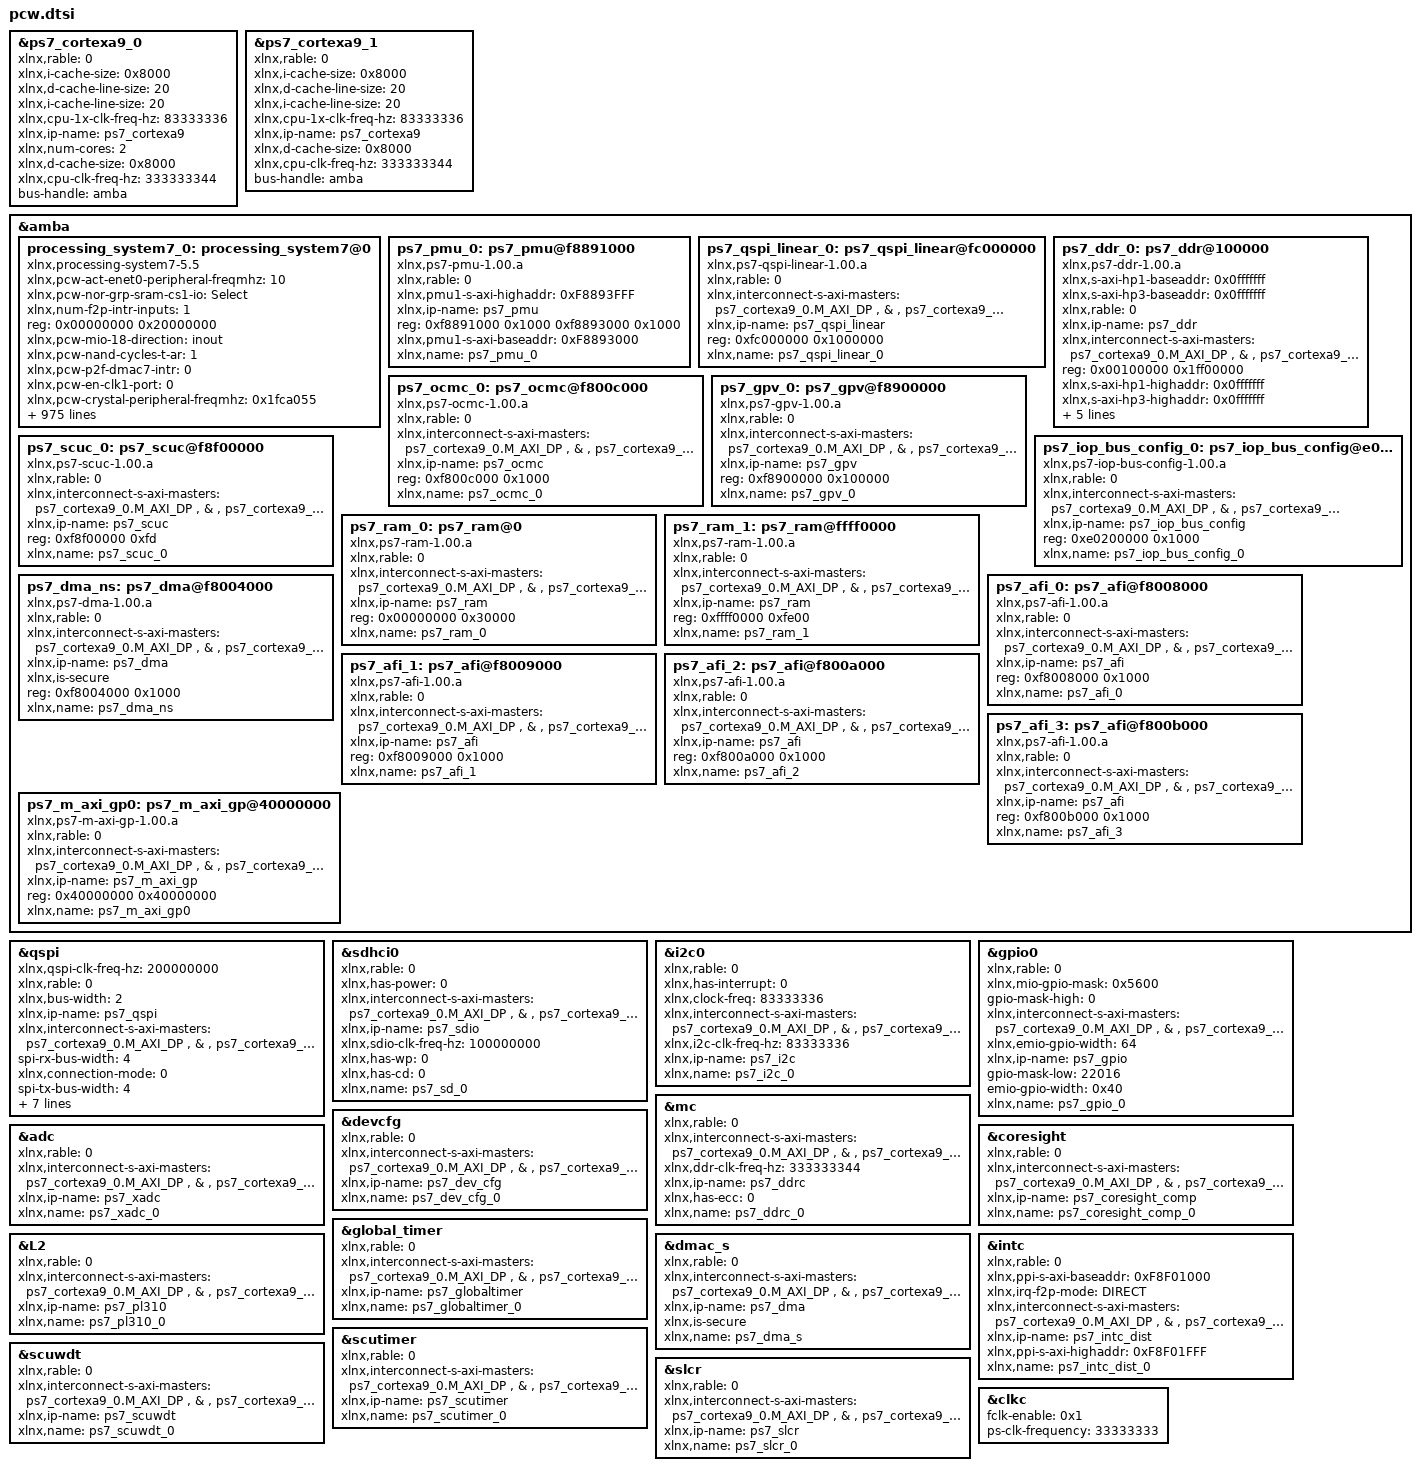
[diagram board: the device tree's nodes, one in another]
	&ps7_cortexa9_0 {
		xlnx,rable = <0>;
		xlnx,i-cache-size = <0x8000>;
		xlnx,d-cache-line-size = <20>;
		xlnx,i-cache-line-size = <20>;
		xlnx,cpu-1x-clk-freq-hz = <83333336>;
		xlnx,ip-name = "ps7_cortexa9";
		xlnx,num-cores = <2>;
		xlnx,d-cache-size = <0x8000>;
		xlnx,cpu-clk-freq-hz = <333333344>;
		bus-handle = <&amba>;
	};
	&ps7_cortexa9_1 {
		xlnx,rable = <0>;
		xlnx,i-cache-size = <0x8000>;
		xlnx,d-cache-line-size = <20>;
		xlnx,i-cache-line-size = <20>;
		xlnx,cpu-1x-clk-freq-hz = <83333336>;
		xlnx,ip-name = "ps7_cortexa9";
		xlnx,d-cache-size = <0x8000>;
		xlnx,cpu-clk-freq-hz = <333333344>;
		bus-handle = <&amba>;
	};
	&amba {
		processing_system7_0: processing_system7@0 {
			xlnx,pcw-act-enet0-peripheral-freqmhz = <10>;
			xlnx,pcw-nor-grp-sram-cs1-io = "<Select>";
			xlnx,num-f2p-intr-inputs = <1>;
			reg = <0x00000000 0x20000000>;
			xlnx,pcw-mio-18-direction = "inout";
			xlnx,pcw-nand-cycles-t-ar = <1>;
			xlnx,pcw-p2f-dmac7-intr = <0>;
			xlnx,pcw-en-clk1-port = <0>;
			xlnx,pcw-crystal-peripheral-freqmhz = <0x1fca055>;
			xlnx,pcw-nor-grp-sram-cs1-enable = <0>;
			xlnx,pcw-uiparam-ddr-dq-1-package-length = <0x4366e20>;
			xlnx,pcw-act-wdt-peripheral-freqmhz = <0x4f790d8>;
			xlnx,pcw-p2f-dmac4-intr = <0>;
			xlnx,pcw-s-axi-hp3-id-width = <6>;
			xlnx,pcw-en-emio-uart0 = <0>;
			xlnx,pcw-en-emio-uart1 = <0>;
			xlnx,pcw-ddr-hpr-to-critical-priority-level = <15>;
			xlnx,pcw-enet-reset-polarity = "Active , Low";
			xlnx,pcw-mio-5-direction = "inout";
			xlnx,pcw-p2f-dmac1-intr = <0>;
			xlnx,pcw-sd0-grp-cd-enable = <0>;
			xlnx,pcw-act-fpga1-peripheral-freqmhz = <10>;
			xlnx,pcw-mio-24-iotype = "LVCMOS , 3.3V";
			xlnx,pcw-ddr-port1-hpr-enable = <0>;
			xlnx,pcw-cpu-peripheral-clksrc = "ARM , PLL";
			xlnx,pcw-mio-53-pullup = "enabled";
			xlnx,pcw-use-axi-nonsecure = <0>;
			xlnx,pcw-spi1-grp-ss0-io = "<Select>";
			xlnx,pcw-uiparam-ddr-dqs-1-propogation-delay = <160>;
			xlnx,pcw-nor-cs1-t-pc = <1>;
			xlnx,pcw-s-axi-gp0-id-width = <6>;
			xlnx,pcw-trace-grp-8bit-io = "<Select>";
			xlnx,pcw-ttc-peripheral-freqmhz = <50>;
			xlnx,pcw-uart0-baseaddr = <0xE0000000>;
			xlnx,pcw-ftm-cti-out0 = "<Select>";
			xlnx,pcw-ttc1-clk0-peripheral-divisor0 = <1>;
			xlnx,pcw-uiparam-ddr-clock-stop-en = <0>;
			xlnx,pcw-ftm-cti-out1 = "<Select>";
			xlnx,pcw-mio-28-direction = "inout";
			xlnx,pcw-en-ttc0 = <0>;
			xlnx,pcw-ftm-cti-out2 = "<Select>";
			xlnx,pcw-mio-11-pullup = "enabled";
			xlnx,pcw-en-ttc1 = <0>;
			xlnx,pcw-ftm-cti-out3 = "<Select>";
			xlnx,pcw-m-axi-gp0-thread-id-width = <12>;
			xlnx,pcw-nor-sram-cs1-t-ceoe = <1>;
			xlnx,pcw-nor-grp-sram-int-enable = <0>;
			xlnx,pcw-can-peripheral-clksrc = "IO , PLL";
			xlnx,pcw-ttc1-clk0-peripheral-clksrc = "CPU_1X";
			xlnx,mio-primitive = <54>;
			xlnx,pcw-gp0-num-write-threads = <4>;
			xlnx,pcw-mio-4-iotype = "LVCMOS , 3.3V";
			xlnx,pcw-mio-41-iotype = "LVCMOS , 3.3V";
			xlnx,pcw-nor-cs1-t-rc = <11>;
			xlnx,pcw-i2c0-grp-int-enable = <0>;
			xlnx,pcw-ddr-port2-hpr-enable = <0>;
			xlnx,pcw-act-tpiu-peripheral-freqmhz = <200>;
			xlnx,pcw-package-name = "clg400";
			xlnx,pcw-s-axi-hp0-id-width = <6>;
			xlnx,pcw-package-ddr-dqs-to-clk-delay-0 = <0x153d8>;
			xlnx,pcw-uiparam-ddr-dqs-3-length-mm = <0>;
			xlnx,pcw-package-ddr-dqs-to-clk-delay-1 = <0x29810>;
			xlnx,pcw-qspi-grp-single-ss-enable = <1>;
			xlnx,pcw-act-usb0-peripheral-freqmhz = <60>;
			xlnx,pcw-mio-27-pullup = "enabled";
			xlnx,pcw-package-ddr-dqs-to-clk-delay-2 = <0x3a980>;
			xlnx,pcw-sdio0-baseaddr = <0xE0100000>;
			xlnx,pcw-mio-38-direction = "inout";
			xlnx,pcw-package-ddr-dqs-to-clk-delay-3 = <0x37aa0>;
			xlnx,pcw-en-spi0 = <0>;
			xlnx,pcw-en-spi1 = <0>;
			xlnx,pcw-include-acp-trans-check = <0>;
			xlnx,pcw-ttc1-clk1-peripheral-divisor0 = <1>;
			xlnx,en-emio-pjtag = <0>;
			xlnx,pcw-nor-sram-cs0-we-time = <0>;
			xlnx,pcw-uiparam-ddr-speed-bin = "DDR3_1066F";
			xlnx,pcw-ddr-port3-hpr-enable = <0>;
			xlnx,pcw-irq-f2p-intr = <0>;
			xlnx,pcw-trace-peripheral-enable = <0>;
			xlnx,pcw-enet0-grp-mdio-io = "<Select>";
			xlnx,pcw-mio-15-iotype = "LVCMOS , 3.3V";
			xlnx,pcw-nor-cs1-t-tr = <1>;
			xlnx,pcw-mio-7-pullup = "disabled";
			xlnx,pcw-mio-44-pullup = "enabled";
			xlnx,pcw-uiparam-act-ddr-freq-mhz = <0x13de4360>;
			xlnx,pcw-use-ps-slcr-registers = <0>;
			xlnx,pcw-mio-48-direction = "inout";
			xlnx,pcw-ttc0-clk0-peripheral-divisor0 = <1>;
			xlnx,pcw-trace-grp-4bit-io = "<Select>";
			xlnx,pcw-nor-cs1-t-wc = <11>;
			xlnx,pcw-gpio-peripheral-enable = <0>;
			xlnx,pcw-nor-cs0-t-ceoe = <1>;
			xlnx,pcw-spi-peripheral-clksrc = "IO , PLL";
			xlnx,pcw-p2f-i2c0-intr = <0>;
			xlnx,pcw-uiparam-ddr-clock-2-package-length = <0x34090b8>;
			status = "okay";
			xlnx,pcw-act-can-peripheral-freqmhz = <10>;
			xlnx,pcw-ttc1-clk2-peripheral-divisor0 = <1>;
			xlnx,pcw-mio-32-iotype = "LVCMOS , 3.3V";
			xlnx,pcw-p2f-gpio-intr = <0>;
			xlnx,pcw-ttc0-clk1-peripheral-freqmhz = <0x7f28155>;
			xlnx,pcw-value-silversion = <3>;
			xlnx,pcw-nor-cs1-t-wp = <1>;
			xlnx,pcw-pcap-peripheral-divisor0 = <8>;
			xlnx,pcw-spi1-spi1-io = "<Select>";
			xlnx,pcw-can0-baseaddr = <0xE0008000>;
			xlnx,pcw-wdt-peripheral-freqmhz = <0x7f28155>;
			xlnx,pcw-mio-18-pullup = "enabled";
			xlnx,pcw-uart1-baud-rate = <115200>;
			xlnx,pcw-mio-17-direction = "inout";
			xlnx,pcw-trace-grp-2bit-io = "<Select>";
			xlnx,pcw-ttc0-clk1-peripheral-divisor0 = <1>;
			xlnx,pcw-spi0-grp-ss2-enable = <0>;
			xlnx,pcw-mio-48-iotype = "LVCMOS , 3.3V";
			xlnx,pcw-usb1-baseaddr = <0xE0103000>;
			xlnx,pcw-gp1-num-read-threads = <4>;
			xlnx,pcw-i2c1-highaddr = <0xE0005FFF>;
			xlnx,pcw-i2c1-i2c1-io = "<Select>";
			xlnx,pcw-sd0-sd0-io = "MIO , 40 , .. , 45";
			xlnx,pcw-can0-grp-clk-enable = <0>;
			xlnx,pcw-mio-4-direction = "inout";
			xlnx,pcw-use-s-axi-acp = <0>;
			xlnx,pcw-uart-peripheral-freqmhz = <100>;
			xlnx,pcw-mio-35-pullup = "enabled";
			xlnx,pcw-usb0-highaddr = <0xE0102fff>;
			xlnx,pcw-gpio-baseaddr = <0xE000A000>;
			xlnx,pcw-uiparam-ddr-partno = "MT41K256M16 , RE-125";
			xlnx,pcw-qspi-peripheral-freqmhz = <200>;
			xlnx,pcw-mio-27-direction = "inout";
			xlnx,pcw-mio-52-slew = "slow";
			xlnx,pcw-can0-peripheral-clksrc = "External";
			xlnx,pcw-uiparam-ddr-dram-width = "16 , Bits";
			xlnx,pcw-nand-cycles-t-rc = <11>;
			xlnx,pcw-nand-nand-io = "<Select>";
			xlnx,pcw-nor-grp-sram-cs0-enable = <0>;
			xlnx,pcw-clk1-freq = <10000000>;
			xlnx,pcw-mio-48-slew = "slow";
			xlnx,pcw-m-axi-gp0-freqmhz = <50>;
			xlnx,pcw-ttc0-clk2-peripheral-divisor0 = <1>;
			xlnx,pcw-mio-45-slew = "slow";
			xlnx,pcw-ttc1-highaddr = <0xE0105fff>;
			xlnx,pcw-mio-23-iotype = "LVCMOS , 3.3V";
			xlnx,pcw-mio-42-slew = "slow";
			xlnx,pcw-mio-52-pullup = "enabled";
			xlnx,m-axi-gp1-id-width = <12>;
			xlnx,pcw-fclk-clk1-buf;
			xlnx,pcw-dual-parallel-qspi-data-mode = "<Select>";
			xlnx,pcw-nand-cycles-t-rr = <1>;
			xlnx,pcw-en-rst1-port = <0>;
			xlnx,pcw-mio-38-slew = "slow";
			xlnx,pcw-uiparam-ddr-dqs-2-length-mm = <0>;
			xlnx,pcw-mio-10-pullup = "enabled";
			xlnx,pcw-mio-35-slew = "slow";
			xlnx,pcw-mio-37-direction = "inout";
			xlnx,pcw-nor-sram-cs0-t-ceoe = <1>;
			xlnx,pcw-usb0-usb0-io = "<Select>";
			xlnx,pcw-mio-32-slew = "slow";
			xlnx,pcw-usb1-reset-io = "<Select>";
			xlnx,pcw-enet1-peripheral-freqmhz = "1000 , Mbps";
			xlnx,pcw-uiparam-ddr-clock-2-propogation-delay = <160>;
			xlnx,pcw-qspi-grp-single-ss-io = "MIO , 1 , .. , 6";
			xlnx,pcw-mio-28-slew = "slow";
			xlnx,pcw-mio-3-iotype = "LVCMOS , 3.3V";
			xlnx,pcw-mio-39-iotype = "LVCMOS , 3.3V";
			xlnx,pcw-mio-40-iotype = "LVCMOS , 3.3V";
			xlnx,pcw-nor-cs1-we-time = <0>;
			xlnx,pcw-enet1-reset-enable = <0>;
			xlnx,pcw-mio-25-slew = "slow";
			xlnx,pcw-can0-grp-clk-io = "<Select>";
			xlnx,pcw-spi1-highaddr = <0xE0007FFF>;
			xlnx,pcw-uiparam-ddr-dq-3-length-mm = <0>;
			xlnx,pcw-mio-22-slew = "slow";
			xlnx,pcw-mio-26-pullup = "enabled";
			xlnx,pcw-nand-cycles-t-wc = <11>;
			xlnx,pcw-fpga2-peripheral-freqmhz = <120>;
			xlnx,pcw-mio-18-slew = "slow";
			xlnx,pcw-mio-47-direction = "inout";
			xlnx,pcw-nor-sram-cs0-t-pc = <1>;
			xlnx,pcw-can-peripheral-freqmhz = <100>;
			xlnx,pcw-uiparam-ddr-dq-2-package-length = <0x386bb9c>;
			xlnx,pcw-mio-15-slew = "slow";
			xlnx,s-axi-hp0-data-width = <64>;
			xlnx,emio-gpio-width = <64>;
			xlnx,fclk-clk2-buf;
			xlnx,pcw-mio-12-slew = "slow";
			xlnx,pcw-en-emio-wdt = <0>;
			xlnx,pcw-nand-cycles-t-wp = <1>;
			xlnx,pcw-ttc1-clk0-peripheral-freqmhz = <0x7f28155>;
			xlnx,pcw-ddr-ddr-pll-freqmhz = <0x4f790c08>;
			xlnx,pcw-enet0-reset-enable = <0>;
			xlnx,pcw-preset-bank1-voltage = "LVCMOS , 3.3V";
			xlnx,pcw-can1-grp-clk-io = "<Select>";
			xlnx,pcw-nor-sram-cs0-t-rc = <11>;
			xlnx,pcw-mio-14-iotype = "LVCMOS , 3.3V";
			xlnx,pcw-mio-6-pullup = "disabled";
			xlnx,pcw-enet-reset-enable = <0>;
			xlnx,pcw-mio-43-pullup = "enabled";
			xlnx,pcw-spi0-peripheral-enable = <0>;
			xlnx,pcw-act-ttc0-clk0-peripheral-freqmhz = <0x4f790d8>;
			xlnx,pcw-nor-grp-a25-enable = <0>;
			xlnx,trace-buffer-fifo-size = <128>;
			xlnx,pcw-uiparam-ddr-dq-1-propogation-delay = <160>;
			xlnx,pcw-trace-grp-4bit-enable = <0>;
			xlnx,pcw-qspi-peripheral-enable = <1>;
			xlnx,pcw-dual-stack-qspi-data-mode = "<Select>";
			xlnx,pcw-package-ddr-board-delay0 = <0x3e800>;
			xlnx,s-axi-hp1-data-width = <64>;
			xlnx,pcw-wdt-peripheral-divisor0 = <1>;
			xlnx,pcw-package-ddr-board-delay1 = <0x35b60>;
			xlnx,pcw-package-ddr-board-delay2 = <0x2bf20>;
			xlnx,pcw-uart0-baud-rate = <115200>;
			xlnx,pcw-en-wdt = <0>;
			xlnx,pcw-include-trace-buffer = <0>;
			xlnx,pcw-m-axi-gp0-id-width = <12>;
			xlnx,pcw-mio-16-direction = "inout";
			xlnx,pcw-package-ddr-board-delay3 = <0x2ea18>;
			xlnx,pcw-dci-peripheral-clksrc = "DDR , PLL";
			xlnx,pcw-i2c1-grp-int-enable = <0>;
			xlnx,pcw-p2f-uart1-intr = <0>;
			xlnx,pcw-mio-31-iotype = "LVCMOS , 3.3V";
			xlnx,pcw-usb1-peripheral-enable = <0>;
			xlnx,pcw-act-can0-peripheral-freqmhz = <0x16b4ddc>;
			xlnx,pcw-mio-3-direction = "inout";
			xlnx,pcw-s-axi-hp3-freqmhz = <10>;
			xlnx,pcw-m-axi-gp0-support-narrow-burst = <0>;
			xlnx,pcw-nor-sram-cs0-t-tr = <1>;
			xlnx,pcw-usb1-reset-enable = <0>;
			xlnx,pcw-can1-can1-io = "<Select>";
			xlnx,pcw-mio-17-pullup = "enabled";
			xlnx,pcw-uiparam-ddr-clock-3-length-mm = <39>;
			xlnx,pcw-sd1-peripheral-enable = <0>;
			xlnx,s-axi-hp2-data-width = <64>;
			xlnx,pcw-en-trace = <0>;
			xlnx,pcw-enet1-baseaddr = <0xE000C000>;
			xlnx,pcw-mio-26-direction = "inout";
			xlnx,pcw-nor-sram-cs0-t-wc = <11>;
			xlnx,pcw-spi0-grp-ss1-enable = <0>;
			xlnx,pcw-ttc0-clk1-peripheral-clksrc = "CPU_1X";
			xlnx,pcw-mio-47-iotype = "LVCMOS , 3.3V";
			xlnx,pcw-nand-grp-d8-io = "<Select>";
			xlnx,pcw-nor-grp-cs1-io = "<Select>";
			xlnx,pcw-en-clktrig1-port = <0>;
			xlnx,pcw-i2c-reset-select = "<Select>";
			xlnx,pcw-act-uart-peripheral-freqmhz = <10>;
			xlnx,pcw-enet0-highaddr = <0xE000BFFF>;
			xlnx,pcw-nor-grp-cs1-enable = <0>;
			xlnx,pcw-usb1-peripheral-freqmhz = <60>;
			xlnx,pcw-usb0-reset-enable = <0>;
			xlnx,m-axi-gp1-thread-id-width = <12>;
			xlnx,pcw-nor-sram-cs0-t-wp = <1>;
			xlnx,pcw-mio-34-pullup = "enabled";
			xlnx,pcw-act-qspi-peripheral-freqmhz = <200>;
			xlnx,pcw-sdio-peripheral-valid = <1>;
			xlnx,pcw-en-emio-trace = <0>;
			xlnx,pcw-uart0-grp-full-enable = <0>;
			xlnx,s-axi-hp3-data-width = <64>;
			xlnx,pcw-uiparam-ddr-dqs-1-length-mm = <8>;
			xlnx,pcw-uiparam-ddr-clock-3-package-length = <0x34090b8>;
			xlnx,pcw-mio-36-direction = "inout";
			xlnx,pcw-qspi-qspi-io = "MIO , 1 , .. , 6";
			xlnx,pcw-fclk0-peripheral-clksrc = "IO , PLL";
			xlnx,pcw-nand-cycles-t-clr = <1>;
			xlnx,pcw-pll-bypassmode-enable = <0>;
			xlnx,s-axi-acp-aruser-val = <31>;
			xlnx,pcw-io-io-pll-freqmhz = <1600>;
			xlnx,pcw-mio-22-iotype = "LVCMOS , 3.3V";
			xlnx,pcw-mio-51-pullup = "enabled";
			xlnx,pcw-p2f-sdio1-intr = <0>;
			xlnx,pcw-qspi-grp-fbclk-io = "<Select>";
			xlnx,use-s-axi-gp0 = <0>;
			xlnx,use-s-axi-gp1 = <0>;
			xlnx,pcw-i2c0-peripheral-enable = <1>;
			xlnx,pcw-uiparam-ddr-dq-2-length-mm = <0>;
			xlnx,pcw-nor-grp-sram-cs0-io = "<Select>";
			xlnx,pcw-enet1-grp-mdio-io = "<Select>";
			xlnx,pcw-enet0-peripheral-enable = <0>;
			xlnx,pcw-p2f-usb0-intr = <0>;
			xlnx,pcw-enet1-reset-io = "<Select>";
			xlnx,pcw-mio-46-direction = "inout";
			xlnx,pcw-spi1-grp-ss2-enable = <0>;
			xlnx,pcw-nor-grp-a25-io = "<Select>";
			xlnx,s-axi-hp2-id-width = <6>;
			xlnx,pcw-en-emio-can0 = <0>;
			xlnx,pcw-core1-fiq-intr = <0>;
			xlnx,pcw-en-emio-can1 = <0>;
			xlnx,pcw-mio-2-iotype = "LVCMOS , 3.3V";
			xlnx,pcw-use-dma0 = <0>;
			xlnx,pcw-can1-grp-clk-enable = <0>;
			xlnx,pcw-mio-38-iotype = "LVCMOS , 3.3V";
			xlnx,pcw-use-dma1 = <0>;
			xlnx,pcw-use-dma2 = <0>;
			xlnx,pcw-use-dma3 = <0>;
			xlnx,pcw-usb-reset-select = "<Select>";
			xlnx,pcw-mio-7-slew = "slow";
			xlnx,pcw-ttc1-peripheral-enable = <0>;
			xlnx,use-axi-nonsecure = <0>;
			xlnx,pcw-sd0-grp-pow-enable = <0>;
			xlnx,pcw-mio-4-slew = "slow";
			xlnx,pcw-mio-25-pullup = "enabled";
			xlnx,pcw-uiparam-ddr-dqs-0-propogation-delay = <160>;
			xlnx,pcw-mio-1-slew = "slow";
			xlnx,pcw-trace-grp-32bit-io = "<Select>";
			xlnx,pcw-act-ttc1-clk2-peripheral-freqmhz = <0x4f790d8>;
			xlnx,pcw-spi-peripheral-valid = <0>;
			xlnx,pcw-mio-15-direction = "inout";
			xlnx,pcw-en-ptp-enet0 = <0>;
			xlnx,pcw-act-enet1-peripheral-freqmhz = <10>;
			xlnx,pcw-mio-13-iotype = "LVCMOS , 3.3V";
			xlnx,pcw-en-ptp-enet1 = <0>;
			xlnx,pcw-mio-5-pullup = "disabled";
			xlnx,pcw-en-clk3-port = <0>;
			xlnx,pcw-mio-42-pullup = "enabled";
			xlnx,pcw-sd1-grp-wp-io = "<Select>";
			xlnx,pcw-fpga-fclk3-enable = <0>;
			xlnx,pcw-mio-2-direction = "inout";
			xlnx,pcw-p2f-dmac6-intr = <0>;
			xlnx,pcw-en-clk0-port = <1>;
			xlnx,pcw-s-axi-gp1-id-width = <6>;
			xlnx,pcw-p2f-dmac3-intr = <0>;
			xlnx,s-axi-acp-awuser-val = <31>;
			xlnx,pcw-uart1-baseaddr = <0xE0001000>;
			xlnx,pcw-uiparam-ddr-clock-2-length-mm = <39>;
			xlnx,pcw-p2f-dmac0-intr = <0>;
			xlnx,pcw-uiparam-ddr-bank-addr-count = <3>;
			xlnx,edk-iptype = "PERIPHERAL";
			xlnx,pcw-en-emio-gpio = <0>;
			xlnx,pcw-act-apu-peripheral-freqmhz = <0x13de4360>;
			xlnx,pcw-trace-internal-width = <2>;
			xlnx,pcw-mio-25-direction = "inout";
			xlnx,pcw-act-fpga2-peripheral-freqmhz = <10>;
			xlnx,pcw-uiparam-ddr-row-addr-count = <15>;
			xlnx,pcw-trace-grp-32bit-enable = <0>;
			xlnx,pcw-nor-cs0-t-pc = <1>;
			xlnx,en-emio-enet0 = <0>;
			xlnx,pcw-mio-29-iotype = "LVCMOS , 3.3V";
			xlnx,pcw-mio-30-iotype = "LVCMOS , 3.3V";
			xlnx,pcw-uart0-highaddr = <0xE0000FFF>;
			xlnx,en-emio-enet1 = <0>;
			xlnx,pcw-nor-cs0-we-time = <0>;
			xlnx,use-s-axi-hp0 = <1>;
			xlnx,use-s-axi-hp1 = <0>;
			xlnx,use-s-axi-hp2 = <0>;
			xlnx,use-s-axi-hp3 = <0>;
			xlnx,pcw-enet1-peripheral-clksrc = "IO , PLL";
			xlnx,pcw-s-axi-hp1-id-width = <6>;
			xlnx,pcw-uiparam-ddr-dq-3-package-length = <0x4d8d458>;
			xlnx,pcw-mio-16-pullup = "enabled";
			xlnx,pcw-trace-trace-io = "<Select>";
			xlnx,pcw-use-trace = <0>;
			xlnx,pcw-cpu-cpu-6x4x-max-range = <534>;
			xlnx,pcw-sdio1-baseaddr = <0xE0101000>;
			xlnx,pcw-p2f-enet1-intr = <0>;
			xlnx,pcw-nor-cs0-t-rc = <11>;
			xlnx,pcw-single-qspi-data-mode = "x4";
			xlnx,pcw-uiparam-ddr-dqs-0-length-mm = <0x10e14a0>;
			xlnx,pcw-uiparam-ddr-dqs-0-package-length = <0x608c8d8>;
			xlnx,pcw-mio-35-direction = "inout";
			xlnx,pcw-gpio-mio-gpio-enable = <1>;
			xlnx,pcw-spi0-grp-ss0-enable = <0>;
			xlnx,fclk-clk0-buf;
			xlnx,pcw-mio-9-iotype = "LVCMOS , 3.3V";
			xlnx,pcw-m-axi-gp0-enable-static-remap = <0>;
			xlnx,pcw-mio-46-iotype = "LVCMOS , 3.3V";
			xlnx,pcw-nand-cycles-t-rea = <1>;
			xlnx,pcw-sdio0-highaddr = <0xE0100FFF>;
			xlnx,pcw-act-usb1-peripheral-freqmhz = <60>;
			compatible = "xlnx,processing-system7-5.5";
			xlnx,pcw-fclk3-peripheral-clksrc = "IO , PLL";
			xlnx,pcw-preset-bank0-voltage = "LVCMOS , 3.3V";
			xlnx,pcw-nor-grp-cs0-enable = <0>;
			xlnx,pcw-mio-33-pullup = "enabled";
			xlnx,pcw-trace-pipeline-width = <8>;
			xlnx,pcw-ftm-cti-in0 = "<Select>";
			xlnx,pcw-ftm-cti-in1 = "<Select>";
			xlnx,pcw-ftm-cti-in2 = "<Select>";
			xlnx,pcw-ftm-cti-in3 = "<Select>";
			xlnx,pcw-uiparam-ddr-dq-1-length-mm = <11>;
			xlnx,pcw-mio-45-direction = "inout";
			xlnx,pcw-uart-peripheral-divisor0 = <1>;
			xlnx,use-m-axi-gp0 = <1>;
			xlnx,pcw-mio-primitive = <54>;
			xlnx,use-m-axi-gp1 = <0>;
			xlnx,pcw-ddr-priority-readport-0 = "<Select>";
			xlnx,pcw-ddr-priority-readport-1 = "<Select>";
			xlnx,pcw-en-pjtag = <0>;
			xlnx,pcw-ddr-priority-readport-2 = "<Select>";
			xlnx,pcw-fclk0-peripheral-divisor0 = <8>;
			xlnx,pcw-nor-cs0-t-tr = <1>;
			xlnx,pcw-ddr-priority-readport-3 = "<Select>";
			xlnx,pcw-fclk0-peripheral-divisor1 = <4>;
			xlnx,pcw-gpio-emio-gpio-io = "<Select>";
			xlnx,pcw-smc-peripheral-valid = <0>;
			xlnx,pcw-uart1-peripheral-enable = <0>;
			xlnx,pcw-act-smc-peripheral-freqmhz = <10>;
			xlnx,pcw-m-axi-gp1-enable-static-remap = <0>;
			xlnx,pcw-mio-21-iotype = "LVCMOS , 3.3V";
			xlnx,pcw-mio-49-pullup = "enabled";
			xlnx,pcw-mio-50-pullup = "enabled";
			xlnx,pcw-p2f-cti-intr = <0>;
			xlnx,pcw-mio-tree-signals = "gpio[0]#qspi0_ss_b#qspi0_io[0]#qspi0_io[1]#qspi0_io[2]#qspi0_io[3]/HOLD_B#qspi0_sclk#gpio[7]#gpio[8]#gpio[9]#gpio[10]#gpio[11]#gpio[12]#gpio[13]#gpio[14]#gpio[15]#gpio[16]#gpio[17]#gpio[18]#gpio[19]#gpio[20]#gpio[21]#gpio[22]#gpio[23]#gpio[24]#gpio[25]#gpio[26]#gpio[27]#gpio[28]#gpio[29]#gpio[30]#gpio[31]#gpio[32]#gpio[33]#gpio[34]#gpio[35]#gpio[36]#gpio[37]#gpio[38]#gpio[39]#clk#cmd#data[0]#data[1]#data[2]#data[3]#gpio[46]#gpio[47]#gpio[48]#gpio[49]#scl#sda#gpio[52]#gpio[53]";
			xlnx,pcw-nor-cs0-t-wc = <11>;
			xlnx,pcw-p2f-smc-intr = <0>;
			xlnx,pcw-qspi-grp-ss1-enable = <0>;
			xlnx,pcw-s-axi-hp2-freqmhz = <10>;
			xlnx,pcw-spi0-grp-ss2-io = "<Select>";
			xlnx,pcw-can1-baseaddr = <0xE0009000>;
			xlnx,pcw-uiparam-ddr-col-addr-count = <10>;
			xlnx,pcw-ddr-lpr-to-critical-priority-level = <2>;
			xlnx,pcw-armpll-ctrl-fbdiv = <40>;
			xlnx,pcw-spi1-grp-ss1-enable = <0>;
			xlnx,pcw-en-emio-pjtag = <0>;
			xlnx,pcw-uiparam-ddr-high-temp = "Normal , (0-85)";
			xlnx,pcw-uiparam-ddr-dqs-3-propogation-delay = <160>;
			xlnx,pcw-nor-cs0-t-wp = <1>;
			xlnx,pcw-trace-grp-2bit-enable = <0>;
			xlnx,pcw-ttc0-clk2-peripheral-freqmhz = <0x7f28155>;
			xlnx,pcw-can0-highaddr = <0xE0008FFF>;
			xlnx,pcw-mio-1-iotype = "LVCMOS , 3.3V";
			xlnx,pcw-mio-37-iotype = "LVCMOS , 3.3V";
			xlnx,pcw-use-cross-trigger = <0>;
			xlnx,pcw-mio-14-direction = "inout";
			xlnx,pcw-s-axi-acp-freqmhz = <10>;
			xlnx,pcw-fclk1-peripheral-divisor0 = <1>;
			xlnx,pcw-fclk1-peripheral-divisor1 = <1>;
			xlnx,pcw-ttc0-ttc0-io = "<Select>";
			xlnx,pcw-spi1-grp-ss2-io = "<Select>";
			xlnx,pcw-ttc1-clk2-peripheral-clksrc = "CPU_1X";
			xlnx,pcw-sd0-grp-wp-io = "<Select>";
			xlnx,pcw-i2c-reset-polarity = "Active , Low";
			xlnx,pcw-mio-24-pullup = "enabled";
			xlnx,pcw-ddr-hprlpr-queue-partition = "HPR(0)/LPR(32)";
			xlnx,pcw-apu-peripheral-freqmhz = <333>;
			xlnx,pcw-mio-1-direction = "out";
			xlnx,pcw-tpiu-peripheral-clksrc = "External";
			xlnx,pcw-usb1-highaddr = <0xE0103fff>;
			xlnx,pcw-core0-irq-intr = <0>;
			xlnx,s-axi-acp-id-width = <3>;
			xlnx,pcw-uiparam-ddr-memory-type = "DDR , 3 , (Low , Voltage)";
			xlnx,pcw-uiparam-ddr-clock-1-length-mm = <39>;
			xlnx,pcw-mio-24-direction = "inout";
			xlnx,pcw-gpio-emio-gpio-width = <64>;
			xlnx,pcw-gpio-highaddr = <0xE000AFFF>;
			xlnx,pcw-uiparam-ddr-clock-1-propogation-delay = <160>;
			xlnx,pcw-i2c0-baseaddr = <0xE0004000>;
			xlnx,irq-f2p-mode = "DIRECT";
			xlnx,pcw-mio-12-iotype = "LVCMOS , 3.3V";
			xlnx,pcw-mio-4-pullup = "disabled";
			xlnx,pcw-mio-41-pullup = "enabled";
			xlnx,pcw-clk3-freq = <10000000>;
			xlnx,pcw-can1-peripheral-enable = <0>;
			xlnx,pcw-fclk2-peripheral-divisor0 = <1>;
			xlnx,pcw-mio-51-slew = "slow";
			xlnx,pcw-fclk2-peripheral-divisor1 = <1>;
			xlnx,pcw-fpga-fclk2-enable = <0>;
			xlnx,pcw-clk0-freq = <50000000>;
			xlnx,pcw-mio-47-slew = "slow";
			xlnx,pcw-sdio-peripheral-divisor0 = <16>;
			xlnx,pcw-use-expanded-iop = <0>;
			xlnx,pcw-mio-44-slew = "slow";
			xlnx,pcw-qspi-peripheral-divisor0 = <8>;
			xlnx,pcw-gp0-num-read-threads = <4>;
			xlnx,pcw-en-rst3-port = <0>;
			xlnx,pcw-mio-34-direction = "inout";
			xlnx,pcw-mio-41-slew = "slow";
			xlnx,pcw-tpiu-peripheral-divisor0 = <1>;
			xlnx,pcw-en-rst0-port = <1>;
			xlnx,pcw-mio-28-iotype = "LVCMOS , 3.3V";
			xlnx,pcw-mio-37-slew = "slow";
			xlnx,pcw-sd1-grp-pow-enable = <0>;
			xlnx,pcw-ttc0-baseaddr = <0xE0104000>;
			xlnx,pcw-mio-34-slew = "slow";
			xlnx,pcw-en-emio-sram-int = <0>;
			xlnx,pcw-uiparam-ddr-dqs-to-clk-delay-0 = <0>;
			xlnx,pcw-uiparam-ddr-dqs-to-clk-delay-1 = <0>;
			xlnx,pcw-uiparam-ddr-dqs-to-clk-delay-2 = <0>;
			xlnx,pcw-uiparam-ddr-dqs-to-clk-delay-3 = <0>;
			xlnx,pcw-mio-31-slew = "slow";
			xlnx,pcw-sd1-grp-wp-enable = <0>;
			xlnx,pcw-mio-15-pullup = "enabled";
			xlnx,pcw-fclk3-peripheral-divisor0 = <1>;
			xlnx,pcw-fclk3-peripheral-divisor1 = <1>;
			xlnx,pcw-uiparam-ddr-dq-0-length-mm = <17>;
			xlnx,pcw-mio-27-slew = "slow";
			xlnx,pcw-smc-peripheral-freqmhz = <100>;
			xlnx,pcw-num-f2p-intr-inputs = <1>;
			xlnx,pcw-wdt-wdt-io = "<Select>";
			xlnx,pcw-uiparam-ddr-dq-0-propogation-delay = <160>;
			xlnx,pcw-mio-24-slew = "slow";
			xlnx,pcw-mio-44-direction = "inout";
			xlnx,pcw-fpga0-peripheral-freqmhz = <50>;
			xlnx,pcw-mio-8-iotype = "LVCMOS , 3.3V";
			xlnx,pcw-iopll-ctrl-fbdiv = <48>;
			xlnx,pcw-mio-45-iotype = "LVCMOS , 3.3V";
			xlnx,pcw-p2f-can1-intr = <0>;
			xlnx,pcw-ddr-priority-writeport-0 = "<Select>";
			xlnx,pcw-i2c0-reset-io = "<Select>";
			xlnx,pcw-ddr-priority-writeport-1 = "<Select>";
			xlnx,pcw-ddr-priority-writeport-2 = "<Select>";
			xlnx,pcw-mio-21-slew = "slow";
			xlnx,pcw-ddr-priority-writeport-3 = "<Select>";
			xlnx,pcw-en-can0 = <0>;
			xlnx,pcw-mio-17-slew = "slow";
			xlnx,pcw-en-can1 = <0>;
			xlnx,pcw-fpga3-peripheral-freqmhz = <50>;
			xlnx,pcw-trace-grp-16bit-io = "<Select>";
			xlnx,pcw-cpu-peripheral-divisor0 = <4>;
			xlnx,pcw-m-axi-gp1-support-narrow-burst = <0>;
			xlnx,pcw-mio-32-pullup = "enabled";
			xlnx,pcw-usb0-peripheral-enable = <0>;
			xlnx,pcw-mio-14-slew = "slow";
			xlnx,pcw-spi0-baseaddr = <0xE0006000>;
			xlnx,pcw-uiparam-ddr-train-read-gate = <1>;
			xlnx,gp1-en-modifiable-txn = <1>;
			xlnx,name = "processing_system7_0";
			xlnx,pcw-act-spi-peripheral-freqmhz = <10>;
			xlnx,pcw-mio-11-slew = "slow";
			xlnx,pcw-ttc1-clk1-peripheral-freqmhz = <0x7f28155>;
			xlnx,pcw-en-emio-modem-uart0 = <0>;
			xlnx,pcw-dq-width = <32>;
			xlnx,pcw-en-emio-modem-uart1 = <0>;
			xlnx,pcw-sd0-peripheral-enable = <1>;
			xlnx,pcw-nor-grp-cs0-io = "<Select>";
			xlnx,pcw-can-peripheral-valid = <0>;
			xlnx,pcw-m-axi-gp1-id-width = <12>;
			xlnx,pcw-ttc0-clk0-peripheral-clksrc = "CPU_1X";
			xlnx,pcw-act-ttc0-clk1-peripheral-freqmhz = <0x4f790d8>;
			xlnx,pcw-mio-19-iotype = "LVCMOS , 3.3V";
			xlnx,pcw-mio-20-iotype = "LVCMOS , 3.3V";
			xlnx,pcw-wdt-peripheral-enable = <0>;
			xlnx,pcw-mio-13-direction = "inout";
			xlnx,pcw-enet1-grp-mdio-enable = <0>;
			xlnx,pcw-mio-48-pullup = "enabled";
			xlnx,pcw-sdio-peripheral-clksrc = "IO , PLL";
			xlnx,pcw-p2f-dmac-abort-intr = <0>;
			xlnx,pcw-nor-peripheral-enable = <0>;
			xlnx,pcw-en-sdio0 = <1>;
			xlnx,pcw-en-sdio1 = <0>;
			xlnx,pcw-ddr-peripheral-divisor0 = <4>;
			xlnx,pcw-mio-0-direction = "inout";
			xlnx,pcw-uiparam-ddr-dqs-1-package-length = <0x4bd1ca4>;
			xlnx,pcw-uiparam-ddr-enable = <1>;
			xlnx,pcw-spi1-grp-ss0-enable = <0>;
			xlnx,pcw-usb-reset-polarity = "Active , Low";
			xlnx,pcw-fclk-clk2-buf;
			xlnx,pcw-p2f-uart0-intr = <0>;
			xlnx,pcw-uiparam-ddr-t-rcd = <7>;
			xlnx,ps7-si-rev = "PRODUCTION";
			xlnx,pcw-mio-0-iotype = "LVCMOS , 3.3V";
			xlnx,pcw-uiparam-ddr-clock-0-length-mm = <39>;
			xlnx,pcw-ddr-ram-baseaddr = <0x00100000>;
			xlnx,pcw-mio-36-iotype = "LVCMOS , 3.3V";
			xlnx,pcw-act-can1-peripheral-freqmhz = <0x16b4ddc>;
			xlnx,pcw-cpu-cpu-pll-freqmhz = <0x4f790c08>;
			xlnx,pcw-mio-23-direction = "inout";
			xlnx,pcw-uiparam-ddr-train-write-level = <1>;
			xlnx,pcw-ddr-write-to-critical-priority-level = <2>;
			xlnx,pcw-nand-peripheral-enable = <0>;
			xlnx,pcw-en-gpio = <1>;
			xlnx,pcw-spi0-spi0-io = "<Select>";
			xlnx,pcw-enet1-highaddr = <0xE000CFFF>;
			xlnx,pcw-use-high-ocm = <0>;
			xlnx,pcw-en-emio-sdio0 = <0>;
			xlnx,pcw-mio-23-pullup = "enabled";
			xlnx,pcw-en-emio-sdio1 = <0>;
			xlnx,pcw-gp1-en-modifiable-txn = <1>;
			xlnx,pcw-mio-9-direction = "inout";
			xlnx,pcw-uart-peripheral-clksrc = "IO , PLL";
			xlnx,pcw-en-clktrig3-port = <0>;
			xlnx,pcw-qspi-peripheral-clksrc = "IO , PLL";
			xlnx,pcw-uiparam-ddr-board-delay0 = <0x3d090>;
			xlnx,pcw-uiparam-ddr-board-delay1 = <0x3d090>;
			xlnx,pcw-uiparam-ddr-board-delay2 = <0x3d090>;
			xlnx,pcw-mio-53-iotype = "LVCMOS , 3.3V";
			xlnx,pcw-uiparam-ddr-board-delay3 = <0x3d090>;
			xlnx,pcw-en-clktrig0-port = <0>;
			xlnx,pcw-dm-width = <4>;
			xlnx,pcw-i2c0-i2c0-io = "MIO , 50 , .. , 51";
			xlnx,pcw-mio-33-direction = "inout";
			xlnx,pcw-mio-11-iotype = "LVCMOS , 3.3V";
			xlnx,pcw-mio-3-pullup = "disabled";
			xlnx,fclk-clk3-buf;
			xlnx,pcw-mio-39-pullup = "enabled";
			xlnx,pcw-mio-40-pullup = "enabled";
			xlnx,pcw-uart0-grp-full-io = "<Select>";
			xlnx,pcw-fpga-fclk1-enable = <0>;
			xlnx,pcw-ttc0-peripheral-enable = <0>;
			xlnx,pcw-uiparam-ddr-t-rc = <0x2e7ddb0>;
			xlnx,pcw-uiparam-ddr-adv-enable = <0>;
			xlnx,pcw-i2c-reset-enable = <0>;
			xlnx,pcw-s-axi-hp1-freqmhz = <50>;
			xlnx,use-default-acp-user-val = <0>;
			xlnx,pcw-act-i2c-peripheral-freqmhz = <50>;
			xlnx,pcw-uiparam-ddr-t-faw = <40>;
			xlnx,preset = "None";
			xlnx,pcw-use-proc-event-bus = <0>;
			xlnx,pcw-uiparam-ddr-t-rp = <7>;
			xlnx,pcw-p2f-sdio0-intr = <0>;
			xlnx,pcw-mio-43-direction = "inout";
			xlnx,s-axi-hp3-id-width = <6>;
			xlnx,pcw-mio-27-iotype = "LVCMOS , 3.3V";
			xlnx,pcw-uiparam-ddr-dq-3-propogation-delay = <160>;
			xlnx,pcw-p2f-spi1-intr = <0>;
			xlnx,pcw-spi-peripheral-freqmhz = <0x9ef21aa>;
			xlnx,m-axi-gp0-thread-id-width = <12>;
			xlnx,s-axi-gp0-id-width = <6>;
			xlnx,pcw-mio-14-pullup = "enabled";
			xlnx,pcw-mio-9-slew = "slow";
			xlnx,m-axi-gp0-enable-static-remap = <0>;
			xlnx,pcw-mio-53-direction = "inout";
			xlnx,pcw-mio-6-slew = "slow";
			xlnx,pcw-mio-7-iotype = "LVCMOS , 3.3V";
			xlnx,pcw-mio-44-iotype = "LVCMOS , 3.3V";
			xlnx,pcw-use-fabric-interrupt = <0>;
			xlnx,pcw-act-ttc1-clk0-peripheral-freqmhz = <0x4f790d8>;
			xlnx,pcw-mio-3-slew = "slow";
			xlnx,baseaddr = <0x00000000>;
			xlnx,pcw-sd1-grp-cd-io = "<Select>";
			xlnx,pcw-use-s-axi-gp0 = <0>;
			xlnx,pcw-use-s-axi-gp1 = <0>;
			xlnx,pcw-en-usb0 = <0>;
			xlnx,pcw-mio-0-slew = "slow";
			xlnx,pcw-nor-grp-sram-int-io = "<Select>";
			xlnx,pcw-en-usb1 = <0>;
			xlnx,pcw-mio-12-direction = "inout";
			xlnx,pcw-pjtag-peripheral-enable = <0>;
			xlnx,pcw-pcap-peripheral-clksrc = "IO , PLL";
			xlnx,pcw-m-axi-gp1-thread-id-width = <12>;
			xlnx,pcw-mio-31-pullup = "enabled";
			xlnx,pcw-usb-reset-enable = <0>;
			xlnx,pcw-mio-tree-peripherals = "GPIO#Quad , SPI , Flash#Quad , SPI , Flash#Quad , SPI , Flash#Quad , SPI , Flash#Quad , SPI , Flash#Quad , SPI , Flash#GPIO#GPIO#GPIO#GPIO#GPIO#GPIO#GPIO#GPIO#GPIO#GPIO#GPIO#GPIO#GPIO#GPIO#GPIO#GPIO#GPIO#GPIO#GPIO#GPIO#GPIO#GPIO#GPIO#GPIO#GPIO#GPIO#GPIO#GPIO#GPIO#GPIO#GPIO#GPIO#GPIO#SD , 0#SD , 0#SD , 0#SD , 0#SD , 0#SD , 0#GPIO#GPIO#GPIO#GPIO#I2C , 0#I2C , 0#GPIO#GPIO";
			xlnx,s-axi-hp0-id-width = <6>;
			xlnx,include-trace-buffer = <0>;
			xlnx,pcw-use-cr-fabric = <1>;
			xlnx,pcw-enet0-peripheral-clksrc = "IO , PLL";
			xlnx,package-name = "clg400";
			xlnx,m-axi-gp1-enable-static-remap = <0>;
			xlnx,pcw-en-clk2-port = <0>;
			xlnx,pcw-p2f-dmac5-intr = <0>;
			xlnx,pcw-mio-18-iotype = "LVCMOS , 3.3V";
			xlnx,pcw-mio-22-direction = "inout";
			xlnx,pcw-mio-47-pullup = "enabled";
			xlnx,pcw-uart1-highaddr = <0xE0001FFF>;
			xlnx,pcw-apu-clk-ratio-enable = "4:2:1";
			xlnx,pcw-act-fpga0-peripheral-freqmhz = <50>;
			xlnx,pcw-p2f-dmac2-intr = <0>;
			xlnx,pcw-fclk2-peripheral-clksrc = "IO , PLL";
			xlnx,rable = <1>;
			xlnx,pcw-usb1-usb1-io = "<Select>";
			xlnx,ip-name = "processing_system7";
			xlnx,pcw-mio-8-direction = "out";
			xlnx,pcw-s-axi-hp2-id-width = <6>;
			xlnx,pcw-act-fpga3-peripheral-freqmhz = <10>;
			xlnx,pcw-qspi-grp-fbclk-enable = <0>;
			xlnx,pcw-qspi-grp-io1-io = "<Select>";
			xlnx,pcw-trace-buffer-fifo-size = <128>;
			xlnx,pcw-use-trace-data-edge-detector = <0>;
			xlnx,pcw-mio-35-iotype = "LVCMOS , 3.3V";
			xlnx,pcw-sd1-sd1-io = "<Select>";
			xlnx,pcw-en-enet0 = <0>;
			xlnx,pcw-en-enet1 = <0>;
			xlnx,pcw-mio-32-direction = "inout";
			xlnx,pcw-sd0-grp-wp-enable = <0>;
			xlnx,include-acp-trans-check = <0>;
			xlnx,pcw-sdio1-highaddr = <0xE0101FFF>;
			xlnx,pcw-i2c-peripheral-freqmhz = <0x4f790d8>;
			xlnx,pcw-uart0-peripheral-enable = <0>;
			xlnx,pcw-p2f-enet0-intr = <0>;
			xlnx,pcw-spi0-grp-ss1-io = "<Select>";
			xlnx,pcw-mio-22-pullup = "enabled";
			xlnx,pcw-can0-can0-io = "<Select>";
			xlnx,pcw-s-axi-gp1-freqmhz = <10>;
			xlnx,pcw-en-ddr = <1>;
			xlnx,pcw-qspi-internal-highaddress = <0xFCFFFFFF>;
			xlnx,pcw-mio-52-iotype = "LVCMOS , 3.3V";
			xlnx,pcw-en-emio-enet0 = <0>;
			xlnx,pcw-uiparam-ddr-clock-0-package-length = <0x34090b8>;
			xlnx,pcw-en-emio-enet1 = <0>;
			xlnx,pcw-uiparam-ddr-dqs-2-propogation-delay = <160>;
			xlnx,pcw-mio-42-direction = "inout";
			xlnx,pcw-use-s-axi-hp0 = <1>;
			xlnx,pcw-use-s-axi-hp1 = <0>;
			xlnx,pcw-enet0-peripheral-divisor0 = <1>;
			xlnx,pcw-mio-10-iotype = "LVCMOS , 3.3V";
			xlnx,pcw-use-s-axi-hp2 = <0>;
			xlnx,pcw-enet0-peripheral-divisor1 = <1>;
			xlnx,pcw-mio-2-pullup = "disabled";
			xlnx,pcw-use-s-axi-hp3 = <0>;
			xlnx,pcw-mio-38-pullup = "enabled";
			xlnx,pcw-spi1-grp-ss1-io = "<Select>";
			xlnx,pcw-fpga-fclk0-enable = <1>;
			xlnx,pcw-uiparam-ddr-dqs-2-package-length = <0x39bb4c0>;
			xlnx,pcw-p2f-qspi-intr = <0>;
			xlnx,pcw-ttc1-clk1-peripheral-clksrc = "CPU_1X";
			xlnx,pcw-gp1-num-write-threads = <4>;
			xlnx,pcw-fclk-clk0-buf;
			xlnx,pcw-uiparam-ddr-use-internal-vref = <0>;
			xlnx,trace-buffer-clock-delay = <12>;
			xlnx,pcw-en-4k-timer = <0>;
			xlnx,pcw-p2f-i2c1-intr = <0>;
			xlnx,pcw-mio-52-direction = "inout";
			xlnx,pcw-override-basic-clock = <0>;
			xlnx,pcw-mio-26-iotype = "LVCMOS , 3.3V";
			xlnx,pcw-can1-highaddr = <0xE0009FFF>;
			xlnx,dq-width = <32>;
			xlnx,pcw-s-axi-hp0-data-width = <64>;
			xlnx,pcw-en-emio-i2c0 = <0>;
			xlnx,pcw-ttc0-clk0-peripheral-freqmhz = <0x7f28155>;
			xlnx,use-s-axi-acp = <0>;
			xlnx,pcw-en-emio-i2c1 = <0>;
			xlnx,pcw-sd0-grp-cd-io = "<Select>";
			xlnx,pcw-uiparam-ddr-clock-0-propogation-delay = <160>;
			xlnx,pcw-pcap-peripheral-freqmhz = <200>;
			xlnx,pcw-act-dci-peripheral-freqmhz = <0x9a2113>;
			xlnx,pcw-mio-11-direction = "inout";
			xlnx,pcw-enet1-peripheral-divisor0 = <1>;
			xlnx,pcw-use-default-acp-user-val = <0>;
			xlnx,pcw-ddrpll-ctrl-fbdiv = <40>;
			xlnx,pcw-enet1-peripheral-divisor1 = <1>;
			xlnx,pcw-mio-13-pullup = "enabled";
			xlnx,pcw-ps7-si-rev = "PRODUCTION";
			xlnx,pcw-can0-peripheral-enable = <0>;
			xlnx,pcw-use-m-axi-gp0 = <1>;
			xlnx,pcw-en-emio-cd-sdio0 = <0>;
			xlnx,pcw-uart0-uart0-io = "<Select>";
			xlnx,pcw-use-m-axi-gp1 = <0>;
			xlnx,pcw-en-emio-cd-sdio1 = <0>;
			xlnx,pcw-core1-irq-intr = <0>;
			xlnx,pcw-mio-6-iotype = "LVCMOS , 3.3V";
			xlnx,pcw-mio-43-iotype = "LVCMOS , 3.3V";
			xlnx,pcw-i2c1-reset-enable = <0>;
			xlnx,pcw-s-axi-hp1-data-width = <64>;
			xlnx,pcw-trace-grp-8bit-enable = <0>;
			xlnx,dqs-width = <4>;
			xlnx,pcw-i2c1-baseaddr = <0xE0005000>;
			xlnx,fclk-clk1-buf;
			xlnx,pcw-mio-21-direction = "inout";
			xlnx,pcw-mio-29-pullup = "enabled";
			xlnx,pcw-mio-30-pullup = "enabled";
			xlnx,trace-internal-width = <2>;
			xlnx,pcw-s-axi-hp0-freqmhz = <50>;
			xlnx,pcw-usb0-baseaddr = <0xE0102000>;
			xlnx,pcw-i2c0-highaddr = <0xE0004FFF>;
			xlnx,pcw-mio-7-direction = "out";
			xlnx,pcw-i2c0-reset-enable = <0>;
			xlnx,pcw-mio-53-slew = "slow";
			xlnx,pcw-sdio-peripheral-freqmhz = <100>;
			xlnx,pcw-uart1-uart1-io = "<Select>";
			xlnx,pcw-dqs-width = <4>;
			xlnx,pcw-s-axi-hp2-data-width = <64>;
			xlnx,pcw-clk2-freq = <10000000>;
			xlnx,pcw-mio-49-slew = "slow";
			xlnx,pcw-mio-50-slew = "slow";
			xlnx,pcw-mio-17-iotype = "LVCMOS , 3.3V";
			xlnx,pcw-en-emio-ttc0 = <0>;
			xlnx,pcw-mio-9-pullup = "enabled";
			xlnx,pcw-en-emio-ttc1 = <0>;
			xlnx,pcw-mio-46-pullup = "enabled";
			xlnx,pcw-mio-31-direction = "inout";
			xlnx,pcw-mio-46-slew = "slow";
			xlnx,pcw-sd1-grp-cd-enable = <0>;
			xlnx,dm-width = <4>;
			xlnx,pcw-ttc1-baseaddr = <0xE0105000>;
			xlnx,pcw-i2c0-grp-int-io = "<Select>";
			xlnx,pcw-mio-43-slew = "slow";
			xlnx,pcw-use-axi-fabric-idle = <0>;
			xlnx,pcw-en-rst2-port = <0>;
			xlnx,pcw-gpio-emio-gpio-enable = <0>;
			xlnx,pcw-mio-39-slew = "slow";
			xlnx,pcw-mio-40-slew = "slow";
			xlnx,gp0-en-modifiable-txn = <1>;
			xlnx,pcw-uart1-grp-full-io = "<Select>";
			xlnx,pcw-uart-peripheral-valid = <0>;
			xlnx,pcw-mio-36-slew = "slow";
			xlnx,pcw-ttc0-highaddr = <0xE0104fff>;
			xlnx,pcw-uiparam-ddr-dq-0-package-length = <0x63b19b4>;
			xlnx,pcw-s-axi-hp3-data-width = <64>;
			xlnx,pcw-enet0-peripheral-freqmhz = "1000 , Mbps";
			xlnx,trace-pipeline-width = <8>;
			xlnx,m-axi-gp0-id-width = <12>;
			xlnx,pcw-mio-33-slew = "slow";
			xlnx,pcw-mio-34-iotype = "LVCMOS , 3.3V";
			xlnx,pcw-use-coresight = <0>;
			xlnx,pcw-uiparam-ddr-bus-width = "16 , Bit";
			xlnx,pcw-en-emio-spi0 = <0>;
			xlnx,pcw-en-emio-spi1 = <0>;
			xlnx,pcw-i2c1-reset-io = "<Select>";
			xlnx,pcw-mio-29-slew = "slow";
			xlnx,pcw-mio-30-slew = "slow";
			xlnx,pcw-mio-41-direction = "inout";
			xlnx,pcw-use-debug = <0>;
			xlnx,pcw-smc-peripheral-divisor0 = <1>;
			xlnx,pcw-i2c1-grp-int-io = "<Select>";
			xlnx,pcw-mio-26-slew = "slow";
			xlnx,pcw-s-axi-acp-aruser-val = <31>;
			xlnx,pcw-uiparam-ddr-t-ras-min = <35>;
			xlnx,pcw-can1-peripheral-clksrc = "External";
			xlnx,pcw-irq-f2p-mode = "DIRECT";
			xlnx,pcw-mio-21-pullup = "enabled";
			xlnx,pcw-usb0-reset-io = "<Select>";
			xlnx,pcw-mio-23-slew = "slow";
			xlnx,pcw-uiparam-ddr-train-data-eye = <1>;
			xlnx,pcw-spi1-baseaddr = <0xE0007000>;
			xlnx,pcw-p2f-can0-intr = <0>;
			xlnx,pcw-fpga1-peripheral-freqmhz = <32>;
			xlnx,pcw-s-axi-acp-id-width = <3>;
			xlnx,pcw-smc-peripheral-clksrc = "IO , PLL";
			xlnx,pcw-mio-19-slew = "slow";
			xlnx,pcw-mio-20-slew = "slow";
			xlnx,pcw-nand-grp-d8-enable = <0>;
			xlnx,pcw-nor-sram-cs1-t-pc = <1>;
			xlnx,pcw-mio-51-iotype = "LVCMOS , 3.3V";
			xlnx,pcw-enet-reset-select = "<Select>";
			xlnx,pcw-mio-16-slew = "slow";
			xlnx,pcw-dci-peripheral-freqmhz = <0x9b0398>;
			xlnx,pcw-spi0-highaddr = <0xE0006FFF>;
			xlnx,pcw-mio-13-slew = "slow";
			xlnx,pcw-mio-51-direction = "inout";
			xlnx,pcw-mio-1-pullup = "enabled";
			xlnx,pcw-mio-10-slew = "slow";
			xlnx,pcw-mio-37-pullup = "enabled";
			xlnx,pcw-nor-sram-cs1-t-rc = <11>;
			xlnx,pcw-ttc1-clk2-peripheral-freqmhz = <0x7f28155>;
			xlnx,pcw-mio-10-direction = "inout";
			xlnx,pcw-uiparam-ddr-clock-3-propogation-delay = <160>;
			xlnx,pcw-use-ddr-bypass = <0>;
			xlnx,pcw-en-modem-uart0 = <0>;
			xlnx,pcw-en-modem-uart1 = <0>;
			xlnx,pcw-trace-grp-16bit-enable = <0>;
			xlnx,pcw-uiparam-ddr-freq-mhz = <333>;
			xlnx,pcw-gp0-en-modifiable-txn = <1>;
			xlnx,pcw-nor-sram-cs1-we-time = <0>;
			xlnx,pcw-act-ttc0-clk2-peripheral-freqmhz = <0x4f790d8>;
			xlnx,pcw-uiparam-ddr-ecc = "Disabled";
			xlnx,pcw-mio-25-iotype = "LVCMOS , 3.3V";
			xlnx,pcw-act-pcap-peripheral-freqmhz = <200>;
			xlnx,pcw-uart1-grp-full-enable = <0>;
			xlnx,pcw-ddr-peripheral-clksrc = "DDR , PLL";
			xlnx,pcw-mio-19-direction = "inout";
			xlnx,pcw-mio-20-direction = "inout";
			xlnx,pcw-mio-12-pullup = "enabled";
			xlnx,pcw-ddr-ram-highaddr = <0x1FFFFFFF>;
			xlnx,en-emio-trace = <0>;
			xlnx,pcw-nor-sram-cs1-t-tr = <1>;
			xlnx,pcw-nor-nor-io = "<Select>";
			xlnx,pcw-s-axi-gp0-freqmhz = <10>;
			xlnx,pcw-spi-peripheral-divisor0 = <1>;
			xlnx,pcw-trace-buffer-clock-delay = <12>;
			xlnx,pcw-uiparam-ddr-clock-1-package-length = <0x34090b8>;
			xlnx,pcw-mio-5-iotype = "LVCMOS , 3.3V";
			xlnx,pcw-mio-6-direction = "out";
			xlnx,pcw-mio-42-iotype = "LVCMOS , 3.3V";
			xlnx,pcw-s-axi-acp-awuser-val = <31>;
			xlnx,pcw-use-expanded-ps-slcr-registers = <0>;
			xlnx,pcw-uiparam-ddr-cwl = <6>;
			xlnx,pcw-spi1-peripheral-enable = <0>;
			xlnx,pcw-nor-sram-cs1-t-wc = <11>;
			xlnx,pcw-tpiu-peripheral-freqmhz = <200>;
			xlnx,pcw-pjtag-pjtag-io = "<Select>";
			xlnx,pcw-wdt-peripheral-clksrc = "CPU_1X";
			xlnx,pcw-uiparam-ddr-dq-2-propogation-delay = <160>;
			xlnx,pcw-uiparam-ddr-dqs-3-package-length = <0x447256c>;
			xlnx,pcw-mio-28-pullup = "enabled";
			xlnx,pcw-mio-29-direction = "inout";
			xlnx,pcw-mio-30-direction = "inout";
			xlnx,pcw-en-clktrig2-port = <0>;
			xlnx,pcw-enet0-grp-mdio-enable = <0>;
			xlnx,pcw-usb0-peripheral-freqmhz = <60>;
			xlnx,pcw-enet0-baseaddr = <0xE000B000>;
			xlnx,pcw-nor-sram-cs1-t-wp = <1>;
			xlnx,pcw-act-ttc-peripheral-freqmhz = <50>;
			xlnx,pcw-act-sdio-peripheral-freqmhz = <100>;
			xlnx,pcw-import-board-preset = "None";
			xlnx,pcw-mio-16-iotype = "LVCMOS , 3.3V";
			xlnx,pcw-mio-8-pullup = "disabled";
			xlnx,pcw-enet0-enet0-io = "<Select>";
			xlnx,pcw-mio-45-pullup = "enabled";
			xlnx,pcw-mio-39-direction = "inout";
			xlnx,pcw-mio-40-direction = "inout";
			xlnx,pcw-uiparam-ddr-device-capacity = "4096 , MBits";
			xlnx,pcw-uiparam-ddr-al = <0>;
			xlnx,pcw-can-peripheral-divisor0 = <1>;
			xlnx,pcw-can-peripheral-divisor1 = <1>;
			xlnx,use-trace-data-edge-detector = <0>;
			xlnx,pcw-ttc0-clk2-peripheral-clksrc = "CPU_1X";
			xlnx,pcw-nor-cs1-t-ceoe = <1>;
			xlnx,pcw-qspi-grp-io1-enable = <0>;
			xlnx,s-axi-gp1-id-width = <6>;
			xlnx,pcw-uiparam-ddr-bl = <8>;
			xlnx,pcw-peripheral-board-preset = "None";
			xlnx,pcw-en-emio-wp-sdio0 = <0>;
			xlnx,pcw-p2f-usb1-intr = <0>;
			xlnx,pcw-en-emio-wp-sdio1 = <0>;
			xlnx,pcw-m-axi-gp1-freqmhz = <10>;
			xlnx,pcw-p2f-spi0-intr = <0>;
			xlnx,pcw-sd0-grp-pow-io = "<Select>";
			xlnx,pcw-mio-33-iotype = "LVCMOS , 3.3V";
			xlnx,pcw-uiparam-ddr-cl = <7>;
			xlnx,pcw-ttc1-ttc1-io = "<Select>";
			xlnx,pcw-en-smc = <0>;
			xlnx,pcw-fclk-clk3-buf;
			xlnx,pcw-mio-49-direction = "inout";
			xlnx,pcw-mio-50-direction = "inout";
			xlnx,pcw-enet0-reset-io = "<Select>";
			xlnx,pcw-mio-8-slew = "slow";
			xlnx,pcw-mio-19-pullup = "enabled";
			xlnx,pcw-mio-20-pullup = "enabled";
			xlnx,pcw-enet1-enet1-io = "<Select>";
			xlnx,pcw-qspi-grp-ss1-io = "<Select>";
			xlnx,pcw-en-i2c0 = <1>;
			xlnx,pcw-dci-peripheral-divisor0 = <44>;
			xlnx,pcw-en-i2c1 = <0>;
			xlnx,pcw-dci-peripheral-divisor1 = <3>;
			xlnx,pcw-mio-5-slew = "slow";
			xlnx,s-axi-hp1-id-width = <6>;
			xlnx,pcw-core0-fiq-intr = <0>;
			xlnx,pcw-fclk1-peripheral-clksrc = "IO , PLL";
			xlnx,pcw-act-ttc1-clk1-peripheral-freqmhz = <0x4f790d8>;
			xlnx,highaddr = <0x1FFFFFFF>;
			xlnx,pcw-mio-2-slew = "slow";
			xlnx,pcw-en-qspi = <1>;
			xlnx,pcw-mio-49-iotype = "LVCMOS , 3.3V";
			xlnx,pcw-mio-50-iotype = "LVCMOS , 3.3V";
			xlnx,pcw-sd1-grp-pow-io = "<Select>";
			xlnx,pcw-en-uart0 = <0>;
			xlnx,pcw-i2c1-peripheral-enable = <0>;
			xlnx,pcw-en-uart1 = <0>;
			xlnx,pcw-ddr-port0-hpr-enable = <0>;
			xlnx,pcw-mio-0-pullup = "enabled";
			xlnx,pcw-enet1-peripheral-enable = <0>;
			xlnx,pcw-gpio-mio-gpio-io = "MIO";
			xlnx,pcw-mio-36-pullup = "enabled";
			xlnx,pcw-spi0-grp-ss0-io = "<Select>";
		};
		ps7_pmu_0: ps7_pmu@f8891000 {
			xlnx,rable = <0>;
			xlnx,pmu1-s-axi-highaddr = <0xF8893FFF>;
			compatible = "xlnx,ps7-pmu-1.00.a";
			status = "okay";
			xlnx,ip-name = "ps7_pmu";
			reg = <0xf8891000 0x1000 0xf8893000 0x1000>;
			xlnx,pmu1-s-axi-baseaddr = <0xF8893000>;
			xlnx,name = "ps7_pmu_0";
		};
		ps7_qspi_linear_0: ps7_qspi_linear@fc000000 {
			xlnx,rable = <0>;
			compatible = "xlnx,ps7-qspi-linear-1.00.a";
			status = "okay";
			xlnx,interconnect-s-axi-masters = "ps7_cortexa9_0.M_AXI_DP , & , ps7_cortexa9_1.M_AXI_DP";
			xlnx,ip-name = "ps7_qspi_linear";
			reg = <0xfc000000 0x1000000>;
			xlnx,name = "ps7_qspi_linear_0";
		};
		ps7_ddr_0: ps7_ddr@100000 {
			compatible = "xlnx,ps7-ddr-1.00.a";
			xlnx,s-axi-hp1-baseaddr = <0x0fffffff>;
			xlnx,s-axi-hp3-baseaddr = <0x0fffffff>;
			xlnx,rable = <0>;
			xlnx,ip-name = "ps7_ddr";
			xlnx,interconnect-s-axi-masters = "ps7_cortexa9_0.M_AXI_DP , & , ps7_cortexa9_1.M_AXI_DP";
			reg = <0x00100000 0x1ff00000>;
			xlnx,s-axi-hp1-highaddr = <0x0fffffff>;
			xlnx,s-axi-hp3-highaddr = <0x0fffffff>;
			xlnx,s-axi-hp0-baseaddr = <0x0fffffff>;
			xlnx,s-axi-hp2-baseaddr = <0x0fffffff>;
			status = "okay";
			xlnx,s-axi-hp0-highaddr = <0x0fffffff>;
			xlnx,s-axi-hp2-highaddr = <0x0fffffff>;
			xlnx,name = "ps7_ddr_0";
		};
		ps7_ocmc_0: ps7_ocmc@f800c000 {
			xlnx,rable = <0>;
			compatible = "xlnx,ps7-ocmc-1.00.a";
			status = "okay";
			xlnx,interconnect-s-axi-masters = "ps7_cortexa9_0.M_AXI_DP , & , ps7_cortexa9_1.M_AXI_DP";
			xlnx,ip-name = "ps7_ocmc";
			reg = <0xf800c000 0x1000>;
			xlnx,name = "ps7_ocmc_0";
		};
		ps7_gpv_0: ps7_gpv@f8900000 {
			xlnx,rable = <0>;
			compatible = "xlnx,ps7-gpv-1.00.a";
			status = "okay";
			xlnx,interconnect-s-axi-masters = "ps7_cortexa9_0.M_AXI_DP , & , ps7_cortexa9_1.M_AXI_DP";
			xlnx,ip-name = "ps7_gpv";
			reg = <0xf8900000 0x100000>;
			xlnx,name = "ps7_gpv_0";
		};
		ps7_scuc_0: ps7_scuc@f8f00000 {
			xlnx,rable = <0>;
			compatible = "xlnx,ps7-scuc-1.00.a";
			status = "okay";
			xlnx,interconnect-s-axi-masters = "ps7_cortexa9_0.M_AXI_DP , & , ps7_cortexa9_1.M_AXI_DP";
			xlnx,ip-name = "ps7_scuc";
			reg = <0xf8f00000 0xfd>;
			xlnx,name = "ps7_scuc_0";
		};
		ps7_iop_bus_config_0: ps7_iop_bus_config@e0200000 {
			xlnx,rable = <0>;
			compatible = "xlnx,ps7-iop-bus-config-1.00.a";
			status = "okay";
			xlnx,interconnect-s-axi-masters = "ps7_cortexa9_0.M_AXI_DP , & , ps7_cortexa9_1.M_AXI_DP";
			xlnx,ip-name = "ps7_iop_bus_config";
			reg = <0xe0200000 0x1000>;
			xlnx,name = "ps7_iop_bus_config_0";
		};
		ps7_ram_0: ps7_ram@0 {
			xlnx,rable = <0>;
			compatible = "xlnx,ps7-ram-1.00.a";
			status = "okay";
			xlnx,interconnect-s-axi-masters = "ps7_cortexa9_0.M_AXI_DP , & , ps7_cortexa9_1.M_AXI_DP";
			xlnx,ip-name = "ps7_ram";
			reg = <0x00000000 0x30000>;
			xlnx,name = "ps7_ram_0";
		};
		ps7_ram_1: ps7_ram@ffff0000 {
			xlnx,rable = <0>;
			compatible = "xlnx,ps7-ram-1.00.a";
			status = "okay";
			xlnx,interconnect-s-axi-masters = "ps7_cortexa9_0.M_AXI_DP , & , ps7_cortexa9_1.M_AXI_DP";
			xlnx,ip-name = "ps7_ram";
			reg = <0xffff0000 0xfe00>;
			xlnx,name = "ps7_ram_1";
		};
		ps7_dma_ns: ps7_dma@f8004000 {
			xlnx,rable = <0>;
			compatible = "xlnx,ps7-dma-1.00.a";
			status = "okay";
			xlnx,interconnect-s-axi-masters = "ps7_cortexa9_0.M_AXI_DP , & , ps7_cortexa9_1.M_AXI_DP";
			xlnx,ip-name = "ps7_dma";
			xlnx,is-secure;
			reg = <0xf8004000 0x1000>;
			xlnx,name = "ps7_dma_ns";
		};
		ps7_afi_0: ps7_afi@f8008000 {
			xlnx,rable = <0>;
			compatible = "xlnx,ps7-afi-1.00.a";
			status = "okay";
			xlnx,interconnect-s-axi-masters = "ps7_cortexa9_0.M_AXI_DP , & , ps7_cortexa9_1.M_AXI_DP";
			xlnx,ip-name = "ps7_afi";
			reg = <0xf8008000 0x1000>;
			xlnx,name = "ps7_afi_0";
		};
		ps7_afi_1: ps7_afi@f8009000 {
			xlnx,rable = <0>;
			compatible = "xlnx,ps7-afi-1.00.a";
			status = "okay";
			xlnx,interconnect-s-axi-masters = "ps7_cortexa9_0.M_AXI_DP , & , ps7_cortexa9_1.M_AXI_DP";
			xlnx,ip-name = "ps7_afi";
			reg = <0xf8009000 0x1000>;
			xlnx,name = "ps7_afi_1";
		};
		ps7_afi_2: ps7_afi@f800a000 {
			xlnx,rable = <0>;
			compatible = "xlnx,ps7-afi-1.00.a";
			status = "okay";
			xlnx,interconnect-s-axi-masters = "ps7_cortexa9_0.M_AXI_DP , & , ps7_cortexa9_1.M_AXI_DP";
			xlnx,ip-name = "ps7_afi";
			reg = <0xf800a000 0x1000>;
			xlnx,name = "ps7_afi_2";
		};
		ps7_afi_3: ps7_afi@f800b000 {
			xlnx,rable = <0>;
			compatible = "xlnx,ps7-afi-1.00.a";
			status = "okay";
			xlnx,interconnect-s-axi-masters = "ps7_cortexa9_0.M_AXI_DP , & , ps7_cortexa9_1.M_AXI_DP";
			xlnx,ip-name = "ps7_afi";
			reg = <0xf800b000 0x1000>;
			xlnx,name = "ps7_afi_3";
		};
		ps7_m_axi_gp0: ps7_m_axi_gp@40000000 {
			xlnx,rable = <0>;
			compatible = "xlnx,ps7-m-axi-gp-1.00.a";
			status = "okay";
			xlnx,interconnect-s-axi-masters = "ps7_cortexa9_0.M_AXI_DP , & , ps7_cortexa9_1.M_AXI_DP";
			xlnx,ip-name = "ps7_m_axi_gp";
			reg = <0x40000000 0x40000000>;
			xlnx,name = "ps7_m_axi_gp0";
		};
	};
	&qspi {
		xlnx,qspi-clk-freq-hz = <200000000>;
		xlnx,rable = <0>;
		xlnx,bus-width = <2>;
		xlnx,ip-name = "ps7_qspi";
		xlnx,interconnect-s-axi-masters = "ps7_cortexa9_0.M_AXI_DP , & , ps7_cortexa9_1.M_AXI_DP";
		spi-rx-bus-width = <4>;
		xlnx,connection-mode = <0>;
		spi-tx-bus-width = <4>;
		status = "okay";
		qspi-fbclk = <0>;
		xlnx,clock-freq = <200000000>;
		xlnx,fb-clk = <0>;
		xlnx,qspi-mode = <0>;
		xlnx,name = "ps7_qspi_0";
		xlnx,qspi-bus-width = <2>;
		is-dual = <0>;
	};
	&sdhci0 {
		xlnx,rable = <0>;
		xlnx,has-power = <0>;
		status = "okay";
		xlnx,interconnect-s-axi-masters = "ps7_cortexa9_0.M_AXI_DP , & , ps7_cortexa9_1.M_AXI_DP";
		xlnx,ip-name = "ps7_sdio";
		xlnx,sdio-clk-freq-hz = <100000000>;
		xlnx,has-wp = <0>;
		xlnx,has-cd = <0>;
		xlnx,name = "ps7_sd_0";
	};
	&i2c0 {
		xlnx,rable = <0>;
		xlnx,has-interrupt = <0>;
		status = "okay";
		xlnx,clock-freq = <83333336>;
		xlnx,interconnect-s-axi-masters = "ps7_cortexa9_0.M_AXI_DP , & , ps7_cortexa9_1.M_AXI_DP";
		xlnx,i2c-clk-freq-hz = <83333336>;
		xlnx,ip-name = "ps7_i2c";
		xlnx,name = "ps7_i2c_0";
	};
	&gpio0 {
		xlnx,rable = <0>;
		xlnx,mio-gpio-mask = <0x5600>;
		status = "okay";
		gpio-mask-high = <0>;
		xlnx,interconnect-s-axi-masters = "ps7_cortexa9_0.M_AXI_DP , & , ps7_cortexa9_1.M_AXI_DP";
		xlnx,emio-gpio-width = <64>;
		xlnx,ip-name = "ps7_gpio";
		gpio-mask-low = <22016>;
		emio-gpio-width = <0x40>;
		xlnx,name = "ps7_gpio_0";
	};
	&mc {
		xlnx,rable = <0>;
		status = "okay";
		xlnx,interconnect-s-axi-masters = "ps7_cortexa9_0.M_AXI_DP , & , ps7_cortexa9_1.M_AXI_DP";
		xlnx,ddr-clk-freq-hz = <333333344>;
		xlnx,ip-name = "ps7_ddrc";
		xlnx,has-ecc = <0>;
		xlnx,name = "ps7_ddrc_0";
	};
	&devcfg {
		xlnx,rable = <0>;
		status = "okay";
		xlnx,interconnect-s-axi-masters = "ps7_cortexa9_0.M_AXI_DP , & , ps7_cortexa9_1.M_AXI_DP";
		xlnx,ip-name = "ps7_dev_cfg";
		xlnx,name = "ps7_dev_cfg_0";
	};
	&adc {
		xlnx,rable = <0>;
		status = "okay";
		xlnx,interconnect-s-axi-masters = "ps7_cortexa9_0.M_AXI_DP , & , ps7_cortexa9_1.M_AXI_DP";
		xlnx,ip-name = "ps7_xadc";
		xlnx,name = "ps7_xadc_0";
	};
	&coresight {
		xlnx,rable = <0>;
		status = "okay";
		xlnx,interconnect-s-axi-masters = "ps7_cortexa9_0.M_AXI_DP , & , ps7_cortexa9_1.M_AXI_DP";
		xlnx,ip-name = "ps7_coresight_comp";
		xlnx,name = "ps7_coresight_comp_0";
	};
	&global_timer {
		xlnx,rable = <0>;
		status = "okay";
		xlnx,interconnect-s-axi-masters = "ps7_cortexa9_0.M_AXI_DP , & , ps7_cortexa9_1.M_AXI_DP";
		xlnx,ip-name = "ps7_globaltimer";
		xlnx,name = "ps7_globaltimer_0";
	};
	&L2 {
		xlnx,rable = <0>;
		status = "okay";
		xlnx,interconnect-s-axi-masters = "ps7_cortexa9_0.M_AXI_DP , & , ps7_cortexa9_1.M_AXI_DP";
		xlnx,ip-name = "ps7_pl310";
		xlnx,name = "ps7_pl310_0";
	};
	&dmac_s {
		xlnx,rable = <0>;
		status = "okay";
		xlnx,interconnect-s-axi-masters = "ps7_cortexa9_0.M_AXI_DP , & , ps7_cortexa9_1.M_AXI_DP";
		xlnx,ip-name = "ps7_dma";
		xlnx,is-secure;
		xlnx,name = "ps7_dma_s";
	};
	&intc {
		xlnx,rable = <0>;
		status = "okay";
		xlnx,ppi-s-axi-baseaddr = <0xF8F01000>;
		xlnx,irq-f2p-mode = "DIRECT";
		xlnx,interconnect-s-axi-masters = "ps7_cortexa9_0.M_AXI_DP , & , ps7_cortexa9_1.M_AXI_DP";
		xlnx,ip-name = "ps7_intc_dist";
		xlnx,ppi-s-axi-highaddr = <0xF8F01FFF>;
		xlnx,name = "ps7_intc_dist_0";
	};
	&scutimer {
		xlnx,rable = <0>;
		status = "okay";
		xlnx,interconnect-s-axi-masters = "ps7_cortexa9_0.M_AXI_DP , & , ps7_cortexa9_1.M_AXI_DP";
		xlnx,ip-name = "ps7_scutimer";
		xlnx,name = "ps7_scutimer_0";
	};
	&scuwdt {
		xlnx,rable = <0>;
		status = "okay";
		xlnx,interconnect-s-axi-masters = "ps7_cortexa9_0.M_AXI_DP , & , ps7_cortexa9_1.M_AXI_DP";
		xlnx,ip-name = "ps7_scuwdt";
		xlnx,name = "ps7_scuwdt_0";
	};
	&slcr {
		xlnx,rable = <0>;
		status = "okay";
		xlnx,interconnect-s-axi-masters = "ps7_cortexa9_0.M_AXI_DP , & , ps7_cortexa9_1.M_AXI_DP";
		xlnx,ip-name = "ps7_slcr";
		xlnx,name = "ps7_slcr_0";
	};
	&clkc {
		fclk-enable = <0x1>;
		ps-clk-frequency = <33333333>;
	};
